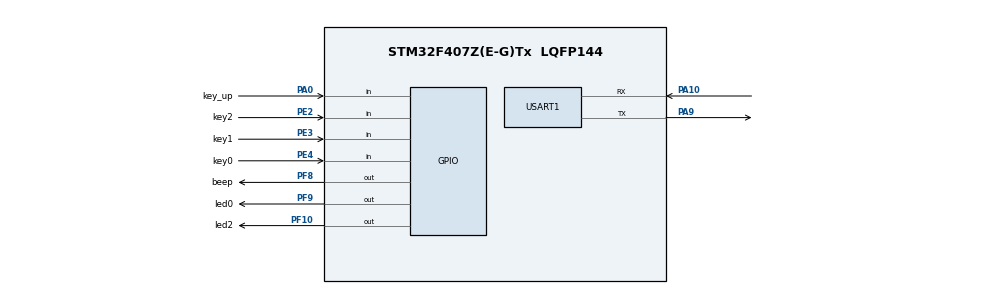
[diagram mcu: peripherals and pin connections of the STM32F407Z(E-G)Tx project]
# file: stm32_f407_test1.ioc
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Mcu.Family=STM32F4
Mcu.Name=STM32F407Z(E-G)Tx
Mcu.Package=LQFP144
NVIC.PriorityGroup=NVIC_PRIORITYGROUP_4
PA0-WKUP.GPIO_Label=key_up
PA0-WKUP.GPIO_PuPd=GPIO_PULLDOWN
PA0-WKUP.Signal=GPIO_Input
PA10.Mode=Asynchronous
PA10.Signal=USART1_RX
PA13.Mode=Serial_Wire
PA13.Signal=SYS_JTMS-SWDIO
PA14.Mode=Serial_Wire
PA14.Signal=SYS_JTCK-SWCLK
PA9.Mode=Asynchronous
PA9.Signal=USART1_TX
PC14-OSC32_IN.Mode=LSE-External-Oscillator
PC14-OSC32_IN.Signal=RCC_OSC32_IN
PC15-OSC32_OUT.Mode=LSE-External-Oscillator
PC15-OSC32_OUT.Signal=RCC_OSC32_OUT
PE2.GPIO_Label=key2
PE2.GPIO_PuPd=GPIO_PULLUP
PE2.Signal=GPIO_Input
PE3.GPIO_Label=key1
PE3.GPIO_PuPd=GPIO_PULLUP
PE3.Signal=GPIO_Input
PE4.GPIO_Label=key0
PE4.GPIO_PuPd=GPIO_PULLUP
PE4.Signal=GPIO_Input
PF10.GPIO_Label=led2
PF10.PinState=GPIO_PIN_SET
PF10.Signal=GPIO_Output
PF8.GPIO_Label=beep
PF8.Signal=GPIO_Output
PF9.GPIO_Label=led0
PF9.PinState=GPIO_PIN_SET
PF9.Signal=GPIO_Output
PH0-OSC_IN.Mode=HSE-External-Oscillator
PH0-OSC_IN.Signal=RCC_OSC_IN
PH1-OSC_OUT.Mode=HSE-External-Oscillator
PH1-OSC_OUT.Signal=RCC_OSC_OUT
ProjectManager.HeapSize=0x200
ProjectManager.StackSize=0x400
ProjectManager.TargetToolchain=CMake
RCC.48MHZClocksFreq_Value=84000000
RCC.AHBFreq_Value=168000000
RCC.APB1CLKDivider=RCC_HCLK_DIV4
RCC.APB1Freq_Value=42000000
RCC.APB1TimFreq_Value=84000000
RCC.APB2CLKDivider=RCC_HCLK_DIV2
RCC.APB2Freq_Value=84000000
RCC.APB2TimFreq_Value=168000000
RCC.CortexFreq_Value=168000000
RCC.HCLKFreq_Value=168000000
RCC.HSE_VALUE=25000000
RCC.HSI_VALUE=16000000
RCC.PLLM=25
RCC.PLLN=336
RCC.PLLSourceVirtual=RCC_PLLSOURCE_HSE
RCC.SYSCLKFreq_VALUE=168000000
RCC.SYSCLKSource=RCC_SYSCLKSOURCE_PLLCLK
RCC.VCOOutputFreq_Value=336000000
USART1.VirtualMode=VM_ASYNC
board=custom

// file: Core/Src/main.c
/* USER CODE BEGIN Header */
/**
  ******************************************************************************
  * @file           : main.c
  * @brief          : Main program body
  ******************************************************************************
  * @attention
  *
  * Copyright (c) 2025 STMicroelectronics.
  * All rights reserved.
  *
  * This software is licensed under terms that can be found in the LICENSE file
  * in the root directory of this software component.
  * If no LICENSE file comes with this software, it is provided AS-IS.
  *
  ******************************************************************************
  */
/* USER CODE END Header */
#include "main.h"
#include "usart.h"
#include "gpio.h"

/* USER CODE BEGIN Includes */
#include "test.h"
#include <stdio.h>  // 添加这一行
/* USER CODE END Includes */

/* USER CODE BEGIN PV */
/* 状态变量定义 */
uint8_t led0_state = 0;  /* led0状态：0-不闪烁，1-闪烁 */
uint8_t led2_state = 0;  /* led2状态：0-不闪烁，1-闪烁 */
uint8_t beep_state = 0;  /* beep状态：0-不工作，1-工作 */

/* 按键标志位 */
uint8_t key0_flag = 0;
uint8_t key1_flag = 0;
uint8_t key2_flag = 0;

/* 计时变量 */
uint32_t led0_timer = 0;
uint32_t led2_timer = 0;
/* USER CODE END PV */

void SystemClock_Config(void);

int main(void)
{

  /* MCU Configuration--------------------------------------------------------*/

  /* Reset of all peripherals, Initializes the Flash interface and the Systick. */
  HAL_Init();

  /* Configure the system clock */
  SystemClock_Config();

  /* Initialize all configured peripherals */
  MX_GPIO_Init();
  MX_USART1_UART_Init();
  /* USER CODE BEGIN 2 */

  int a=test(8,45);
  printf("print number is :a=%d\n",a);
  /* USER CODE END 2 */

  /* Infinite loop */
  /* USER CODE BEGIN WHILE */
  while (1)
  {
    /* 按键检测 */
    if (HAL_GPIO_ReadPin(key0_GPIO_Port, key0_Pin) == GPIO_PIN_RESET) {
      HAL_Delay(30);  /* 消抖 */
      if (HAL_GPIO_ReadPin(key0_GPIO_Port, key0_Pin) == GPIO_PIN_RESET) {
        while (HAL_GPIO_ReadPin(key0_GPIO_Port, key0_Pin) == GPIO_PIN_RESET);  /* 等待按键释放 */
        led0_state ^= 1;  /* 切换状态 */
      }
      printf("key0 pressed, led0_state: %d\n", led0_state);
    }

    if (HAL_GPIO_ReadPin(key1_GPIO_Port, key1_Pin) == GPIO_PIN_RESET) {
      HAL_Delay(20);  /* 消抖 */
      if (HAL_GPIO_ReadPin(key1_GPIO_Port, key1_Pin) == GPIO_PIN_RESET) {
        while (HAL_GPIO_ReadPin(key1_GPIO_Port, key1_Pin) == GPIO_PIN_RESET);  /* 等待按键释放 */
        led2_state ^= 1;  /* 切换状态 */
      }
    }

    if (HAL_GPIO_ReadPin(key2_GPIO_Port, key2_Pin) == GPIO_PIN_RESET) {
      HAL_Delay(20);  /* 消抖 */
      if (HAL_GPIO_ReadPin(key2_GPIO_Port, key2_Pin) == GPIO_PIN_RESET) {
        while (HAL_GPIO_ReadPin(key2_GPIO_Port, key2_Pin) == GPIO_PIN_RESET);  /* 等待按键释放 */
        beep_state ^= 1;  /* 切换状态 */
        HAL_GPIO_WritePin(beep_GPIO_Port, beep_Pin, beep_state ? GPIO_PIN_SET : GPIO_PIN_RESET);
      }
    }

    /* LED闪烁控制 */
    if (led0_state) {
      if (HAL_GetTick() - led0_timer > 200) {  /* 500ms闪烁一次 */
        led0_timer = HAL_GetTick();
        HAL_GPIO_TogglePin(led0_GPIO_Port, led0_Pin);
      }
    } else {
      HAL_GPIO_WritePin(led0_GPIO_Port, led0_Pin, GPIO_PIN_SET);  /* 熄灭 */
    }

    if (led2_state) {
      if (HAL_GetTick() - led2_timer > 200) {  /* 500ms闪烁一次 */
        led2_timer = HAL_GetTick();
        HAL_GPIO_TogglePin(led2_GPIO_Port, led2_Pin);
      }
    } else {
      HAL_GPIO_WritePin(led2_GPIO_Port, led2_Pin, GPIO_PIN_SET);  /* 熄灭 */
    }
    /* USER CODE END WHILE */

  }
}

void SystemClock_Config(void)
{
  RCC_OscInitTypeDef RCC_OscInitStruct = {0};
  RCC_ClkInitTypeDef RCC_ClkInitStruct = {0};

  /** Configure the main internal regulator output voltage
  */
  __HAL_RCC_PWR_CLK_ENABLE();
  __HAL_PWR_VOLTAGESCALING_CONFIG(PWR_REGULATOR_VOLTAGE_SCALE1);

  /** Initializes the RCC Oscillators according to the specified parameters
  * in the RCC_OscInitTypeDef structure.
  */
  RCC_OscInitStruct.OscillatorType = RCC_OSCILLATORTYPE_HSE;
  RCC_OscInitStruct.HSEState = RCC_HSE_ON;
  RCC_OscInitStruct.PLL.PLLState = RCC_PLL_ON;
  RCC_OscInitStruct.PLL.PLLSource = RCC_PLLSOURCE_HSE;
  RCC_OscInitStruct.PLL.PLLM = 8;
  RCC_OscInitStruct.PLL.PLLN = 336;
  RCC_OscInitStruct.PLL.PLLP = RCC_PLLP_DIV2;
  RCC_OscInitStruct.PLL.PLLQ = 4;
  if (HAL_RCC_OscConfig(&RCC_OscInitStruct) != HAL_OK)
  {
    Error_Handler();
  }

  /** Initializes the CPU, AHB and APB buses clocks
  */
  RCC_ClkInitStruct.ClockType = RCC_CLOCKTYPE_HCLK|RCC_CLOCKTYPE_SYSCLK
                              |RCC_CLOCKTYPE_PCLK1|RCC_CLOCKTYPE_PCLK2;
  RCC_ClkInitStruct.SYSCLKSource = RCC_SYSCLKSOURCE_PLLCLK;
  RCC_ClkInitStruct.AHBCLKDivider = RCC_SYSCLK_DIV1;
  RCC_ClkInitStruct.APB1CLKDivider = RCC_HCLK_DIV4;
  RCC_ClkInitStruct.APB2CLKDivider = RCC_HCLK_DIV2;

  if (HAL_RCC_ClockConfig(&RCC_ClkInitStruct, FLASH_LATENCY_5) != HAL_OK)
  {
    Error_Handler();
  }
}

void Error_Handler(void)
{
  __disable_irq();
  while (1)
  {
  }
}
